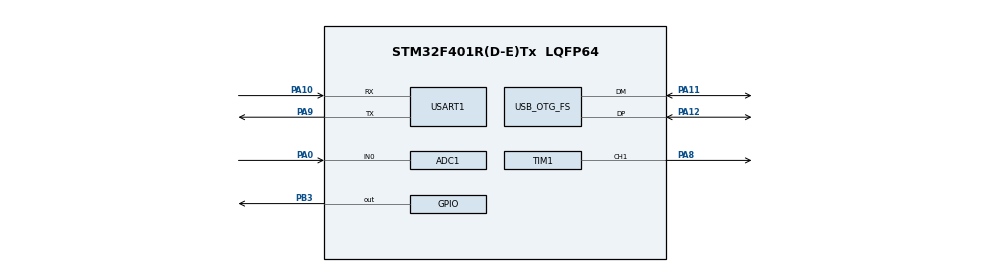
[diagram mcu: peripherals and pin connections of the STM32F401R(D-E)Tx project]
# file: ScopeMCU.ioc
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ADC1.Channel-0\#ChannelRegularConversion=ADC_CHANNEL_0
ADC1.Channel-1\#ChannelRegularConversion=ADC_CHANNEL_VREFINT
ADC1.ContinuousConvMode=DISABLE
ADC1.DMAContinuousRequests=ENABLE
ADC1.ExternalTrigConv=ADC_EXTERNALTRIGCONV_T3_TRGO
ADC1.NbrOfConversion=2
ADC1.NbrOfConversionFlag=1
ADC1.Rank-0\#ChannelRegularConversion=1
ADC1.Rank-1\#ChannelRegularConversion=2
ADC1.SamplingTime-0\#ChannelRegularConversion=ADC_SAMPLETIME_28CYCLES
ADC1.SamplingTime-1\#ChannelRegularConversion=ADC_SAMPLETIME_28CYCLES
ADC1.ScanConvMode=ENABLE
ADC1.master=1
Dma.ADC1.0.Direction=DMA_PERIPH_TO_MEMORY
Dma.ADC1.0.FIFOMode=DMA_FIFOMODE_DISABLE
Dma.ADC1.0.Instance=DMA2_Stream0
Dma.ADC1.0.MemDataAlignment=DMA_MDATAALIGN_HALFWORD
Dma.ADC1.0.MemInc=DMA_MINC_ENABLE
Dma.ADC1.0.Mode=DMA_CIRCULAR
Dma.ADC1.0.PeriphDataAlignment=DMA_PDATAALIGN_HALFWORD
Dma.ADC1.0.PeriphInc=DMA_PINC_DISABLE
Dma.ADC1.0.Priority=DMA_PRIORITY_LOW
Dma.Request0=ADC1
Mcu.Family=STM32F4
Mcu.Name=STM32F401R(D-E)Tx
Mcu.Package=LQFP64
NVIC.ADC_IRQn=true\:0\:0\:false\:false\:true\:true\:true
NVIC.DMA2_Stream0_IRQn=true\:5\:0\:true\:false\:true\:false\:true
NVIC.OTG_FS_IRQn=true\:0\:0\:false\:false\:true\:false\:true
NVIC.PriorityGroup=NVIC_PRIORITYGROUP_4
NVIC.USART1_IRQn=true\:0\:0\:false\:false\:true\:true\:true
PA0-WKUP.Signal=ADCx_IN0
PA10.Mode=Asynchronous
PA10.Signal=USART1_RX
PA11.Mode=Device_Only
PA11.Signal=USB_OTG_FS_DM
PA12.Mode=Device_Only
PA12.Signal=USB_OTG_FS_DP
PA13.Mode=Serial_Wire
PA13.Signal=SYS_JTMS-SWDIO
PA14.Mode=Serial_Wire
PA14.Signal=SYS_JTCK-SWCLK
PA8.Signal=S_TIM1_CH1
PA9.Mode=Asynchronous
PA9.Signal=USART1_TX
PB3.Signal=GPIO_Output
PH0\ -\ OSC_IN.Mode=HSE-External-Oscillator
PH0\ -\ OSC_IN.Signal=RCC_OSC_IN
PH1\ -\ OSC_OUT.Mode=HSE-External-Oscillator
PH1\ -\ OSC_OUT.Signal=RCC_OSC_OUT
ProjectManager.HeapSize=0x200
ProjectManager.StackSize=0x400
ProjectManager.TargetToolchain=SW4STM32
RCC.48MHZClocksFreq_Value=48000000
RCC.AHBFreq_Value=84000000
RCC.APB1CLKDivider=RCC_HCLK_DIV2
RCC.APB1Freq_Value=42000000
RCC.APB1TimFreq_Value=84000000
RCC.APB2Freq_Value=84000000
RCC.APB2TimFreq_Value=84000000
RCC.CortexFreq_Value=84000000
RCC.HCLKFreq_Value=84000000
RCC.HSE_VALUE=16000000
RCC.HSI_VALUE=16000000
RCC.LSE_VALUE=32768
RCC.PLLM=8
RCC.PLLN=168
RCC.PLLP=RCC_PLLP_DIV4
RCC.PLLQ=7
RCC.SYSCLKFreq_VALUE=84000000
RCC.SYSCLKSource=RCC_SYSCLKSOURCE_PLLCLK
RCC.VCOOutputFreq_Value=336000000
SH.ADCx_IN0.0=ADC1_IN0,IN0
SH.S_TIM1_CH1.0=TIM1_CH1,PWM Generation1 CH1
TIM1.AutoReloadPreload=TIM_AUTORELOAD_PRELOAD_ENABLE
TIM1.Channel-PWM\ Generation1\ CH1=TIM_CHANNEL_1
TIM3.AutoReloadPreload=TIM_AUTORELOAD_PRELOAD_ENABLE
TIM3.TIM_MasterOutputTrigger=TIM_TRGO_UPDATE
USART1.VirtualMode=VM_ASYNC
USB_DEVICE.CLASS_NAME_FS=CDC
USB_DEVICE.MANUFACTURER_STRING-CDC_FS=Scope
USB_DEVICE.PRODUCT_STRING_CDC_FS=ScopeMCU
USB_DEVICE.VID-CDC_FS=0x1234
USB_DEVICE.VirtualMode-CDC_FS=Cdc
USB_DEVICE.VirtualModeFS=Cdc_FS
USB_OTG_FS.VirtualMode=Device_Only
VP_ADC1_Vref_Input.Mode=IN-Vrefint
VP_TIM1_VS_ClockSourceINT.Mode=Internal
VP_TIM3_VS_ClockSourceINT.Mode=Internal
VP_USB_DEVICE_VS_USB_DEVICE_CDC_FS.Mode=CDC_FS
board=custom

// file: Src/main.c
/* USER CODE BEGIN Header */
/**
  ******************************************************************************
  * @file           : main.c
  * @brief          : Main program body
  ******************************************************************************
  * @attention
  *
  * <h2><center>&copy; Copyright (c) 2019 STMicroelectronics.
  * All rights reserved.</center></h2>
  *
  * This software component is licensed by ST under BSD 3-Clause license,
  * the "License"; You may not use this file except in compliance with the
  * License. You may obtain a copy of the License at:
  *                        opensource.org/licenses/BSD-3-Clause
  *
  ******************************************************************************
  */
/* USER CODE END Header */

#include "main.h"
#include "adc.h"
#include "dma.h"
#include "tim.h"
#include "usart.h"
#include "usb_device.h"
#include "gpio.h"

/* USER CODE BEGIN Includes */
#include "log.h"
#include "app.h"

/* USER CODE END Includes */

void SystemClock_Config(void);

int main(void)
{

  /* MCU Configuration--------------------------------------------------------*/

  /* Reset of all peripherals, Initializes the Flash interface and the Systick. */
  HAL_Init();

  /* Configure the system clock */
  SystemClock_Config();

  /* USER CODE BEGIN SysInit */
  init();

  /* USER CODE END SysInit */

  /* Initialize all configured peripherals */
  MX_GPIO_Init();
  MX_TIM3_Init();
  MX_USART1_UART_Init();
  MX_DMA_Init();
  MX_ADC1_Init();
  MX_TIM1_Init();
  MX_USB_DEVICE_Init();
  /* USER CODE BEGIN 2 */
  setup();

  /* USER CODE END 2 */

  /* Infinite loop */
  /* USER CODE BEGIN WHILE */
  while (1)
  {
    loop();
    /* USER CODE END WHILE */

  }
}

void SystemClock_Config(void)
{
  RCC_OscInitTypeDef RCC_OscInitStruct = {0};
  RCC_ClkInitTypeDef RCC_ClkInitStruct = {0};
  RCC_PeriphCLKInitTypeDef PeriphClkInit = {0};

  /** Initializes the CPU, AHB and APB busses clocks
  */
  RCC_OscInitStruct.OscillatorType = RCC_OSCILLATORTYPE_HSE;
  RCC_OscInitStruct.HSEState = RCC_HSE_ON;
  RCC_OscInitStruct.HSEPredivValue = RCC_HSE_PREDIV_DIV1;
  RCC_OscInitStruct.HSIState = RCC_HSI_ON;
  RCC_OscInitStruct.PLL.PLLState = RCC_PLL_ON;
  RCC_OscInitStruct.PLL.PLLSource = RCC_PLLSOURCE_HSE;
  RCC_OscInitStruct.PLL.PLLMUL = RCC_PLL_MUL9;
  if (HAL_RCC_OscConfig(&RCC_OscInitStruct) != HAL_OK)
  {
    Error_Handler();
  }
  /** Initializes the CPU, AHB and APB busses clocks
  */
  RCC_ClkInitStruct.ClockType = RCC_CLOCKTYPE_HCLK|RCC_CLOCKTYPE_SYSCLK
                              |RCC_CLOCKTYPE_PCLK1|RCC_CLOCKTYPE_PCLK2;
  RCC_ClkInitStruct.SYSCLKSource = RCC_SYSCLKSOURCE_PLLCLK;
  RCC_ClkInitStruct.AHBCLKDivider = RCC_SYSCLK_DIV1;
  RCC_ClkInitStruct.APB1CLKDivider = RCC_HCLK_DIV2;
  RCC_ClkInitStruct.APB2CLKDivider = RCC_HCLK_DIV1;

  if (HAL_RCC_ClockConfig(&RCC_ClkInitStruct, FLASH_LATENCY_2) != HAL_OK)
  {
    Error_Handler();
  }
  PeriphClkInit.PeriphClockSelection = RCC_PERIPHCLK_ADC|RCC_PERIPHCLK_USB;
  PeriphClkInit.AdcClockSelection = RCC_ADCPCLK2_DIV6;
  PeriphClkInit.UsbClockSelection = RCC_USBCLKSOURCE_PLL_DIV1_5;
  if (HAL_RCCEx_PeriphCLKConfig(&PeriphClkInit) != HAL_OK)
  {
    Error_Handler();
  }
}

void Error_Handler(void)
{
  /* USER CODE BEGIN Error_Handler_Debug */
  /* User can add his own implementation to report the HAL error return state */
  LOGF();
  /* USER CODE END Error_Handler_Debug */
}

#ifdef  USE_FULL_ASSERT
/**
  * @brief  Reports the name of the source file and the source line number
  *         where the assert_param error has occurred.
  * @param  file: pointer to the source file name
  * @param  line: assert_param error line source number
  * @retval None
  */
void assert_failed(uint8_t *file, uint32_t line)
{
  /* USER CODE BEGIN 6 */
  /* User can add his own implementation to report the file name and line number,
     tex: printf("Wrong parameters value: file %s on line %d\r\n", file, line) */
  LOGF("file:%s, line:%lu", file, line);
  /* USER CODE END 6 */
}
#endif /* USE_FULL_ASSERT */

/************************ (C) COPYRIGHT STMicroelectronics *****END OF FILE****/
